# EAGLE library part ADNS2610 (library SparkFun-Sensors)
Optical mouse sensor (SPI)

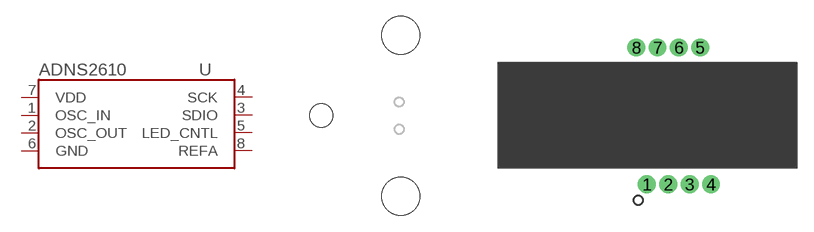
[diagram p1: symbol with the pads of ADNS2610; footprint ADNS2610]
Designator prefix U

## ADNS2610PTH  [ADNS2610]
1  OSC_IN
2  OSC_OUT
3  SDIO
4  SCK
5  LED_CNTL
6  GND
7  VDD
8  REFA

## Footprint ADNS2610 (pad centres in mm)
drill 0.787 pad 1.676: 1 -2.032,-6.477; 2 -0.032,-6.477; 3 1.968,-6.477; 4 3.968,-6.477; 5 2.968,6.323; 6 0.968,6.323; 7 -1.032,6.323; 8 -3.032,6.323
hole 3.556 at -25.044,7.493
hole 3.556 at -25.07,-7.62
hole 2.184 at -32.512,-0.051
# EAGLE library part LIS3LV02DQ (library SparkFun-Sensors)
3-axis 2/6g I2C/SPI accelerometer

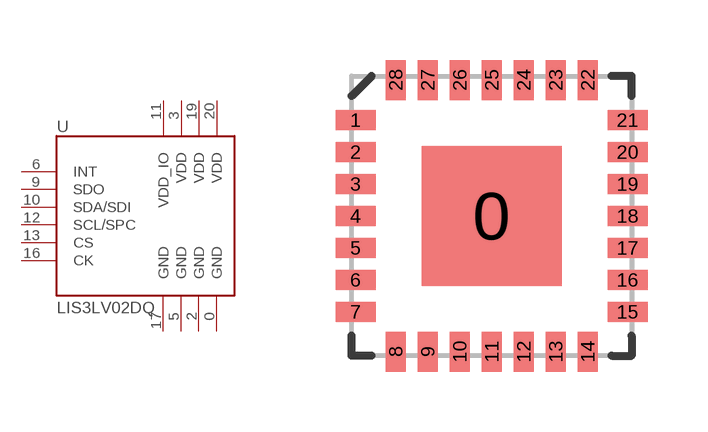
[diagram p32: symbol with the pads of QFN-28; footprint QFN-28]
Designator prefix -

## LIS3LV02DQSMD  [QFN-28]
0  GND  pwr
2  GND  pwr
3  VDD  pwr
5  GND  pwr
6  INT  out
9  SDO  out
10  SDA/SDI
11  VDD_IO  pwr
12  SCL/SPC  in
13  CS  in
16  CK  in
17  GND  pwr
19  VDD  pwr
20  VDD  pwr

## Footprint QFN-28 (pad centres in mm)
smd 3.5 x 3.5: 0 0,0
smd 1 x 0.5: 1 -3.4,2.4; 2 -3.4,1.6; 3 -3.4,0.8; 4 -3.4,0; 5 -3.4,-0.8; 6 -3.4,-1.6; 7 -3.4,-2.4; 15 3.4,-2.4; 16 3.4,-1.6; 17 3.4,-0.8; 18 3.4,0; 19 3.4,0.8; 20 3.4,1.6; 21 3.4,2.4
smd 0.5 x 1: 8 -2.4,-3.4; 9 -1.6,-3.4; 10 -0.8,-3.4; 11 0,-3.4; 12 0.8,-3.4; 13 1.6,-3.4; 14 2.4,-3.4; 22 2.4,3.4; 23 1.6,3.4; 24 0.8,3.4; 25 0,3.4; 26 -0.8,3.4; 27 -1.6,3.4; 28 -2.4,3.4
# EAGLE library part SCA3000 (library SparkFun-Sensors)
2g SPI accelerometer with interrrupt

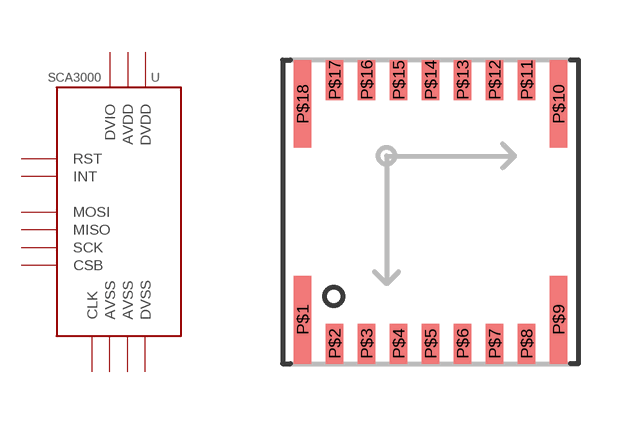
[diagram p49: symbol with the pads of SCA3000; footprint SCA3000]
Designator prefix -

## SCA3000  [SCA3000]
P$2  RST
P$3  INT
P$4  CLK
P$5  DVSS
P$6  DVDD
P$7  DVIO
P$8  CSB
P$11  SCK
P$12  MISO
P$13  MOSI
P$14  AVDD
P$15  AVSS
P$16  AVSS

## Footprint SCA3000 (pad centres in mm)
smd 0.43 x 2.2: P$1 0,0.5; P$9 6.4,0.5; P$10 6.4,5.9; P$18 0,5.9
smd 0.43 x 1: P$2 0.8,-0.1; P$3 1.6,-0.1; P$4 2.4,-0.1; P$5 3.2,-0.1; P$6 4,-0.1; P$7 4.8,-0.1; P$8 5.6,-0.1; P$11 5.6,6.5; P$12 4.8,6.5; P$13 4,6.5; P$14 3.2,6.5; P$15 2.4,6.5; P$16 1.6,6.5; P$17 0.8,6.5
